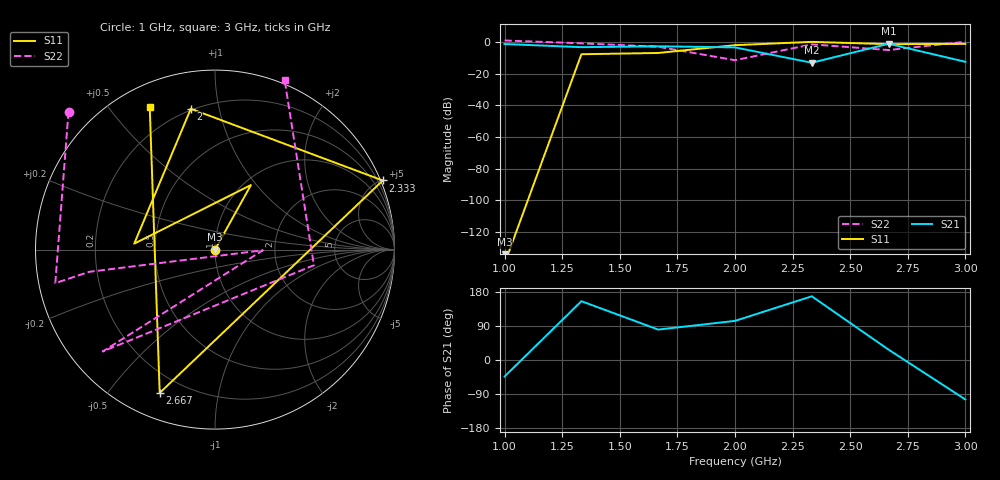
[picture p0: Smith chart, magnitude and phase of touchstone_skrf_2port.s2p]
! Created with skrf 1.9.0 (http://scikit-rf.org).
# Hz S RI R 50.0
!freq ReS11 ImS11 ReS21 ImS21 ReS12 ImS12 ReS22 ImS22
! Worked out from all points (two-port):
!   7 points, 1 GHz to 3 GHz, reference 50 ohm
!   highest |S21| = -1.11 dB at 2.667 GHz (marker M1); lowest = -13.1 dB at 2.333 GHz (marker M2)
!   |S21| within 3 dB of the highest: start of sweep to 2.024 GHz; 2.583 GHz to 2.754 GHz (171.2 MHz wide, 6.41 % of centre)
!   lowest |S11| = -140.0 dB at 1 GHz (marker M3), VSWR 1.00, Z = 50 - j2.5e-10 ohm
!   |S11| at or under -10 dB: start of sweep to 1.328 GHz
!   |S22| runs from -11.5 to 1.0 dB; largest |S21 - S12| = 0.88
!   S11 on the Smith chart (normalised r, x): 1 GHz: 1.00, -0.00; 2 GHz: 0.19, +0.82; 2.333 GHz: -0.15, +5.05; 2.667 GHz: 0.11, -0.68; 3 GHz: 0.09, +0.64
1e9  1e-07 -2.5e-12  0.6285 -0.5962  0 0  -0.8162 0.7689
1.333333e9  0.2002 0.3596  -0.6242 0.2889  0 0  -0.8897 -0.1869
1.666667e9  -0.4501 0.0332  0.1245 0.7242  0 0  -0.6999 -0.1236
2e9  -0.1347 0.7845  -0.1544 0.6587  0 0  0.2664 -0.00389
2.333333e9  0.9349 0.385  -0.2168 0.0457  0 0  -0.6255 -0.5676
2.666667e9  -0.3081 -0.7986  0.7824 0.4039  0 0  0.5511 -0.0871
3e9  -0.3637 0.7955  -0.0582 -0.2298  0 0  0.3875 0.9474
